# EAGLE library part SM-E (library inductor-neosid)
TRANSFORMER SMD converter and transformer acc. to customer specification

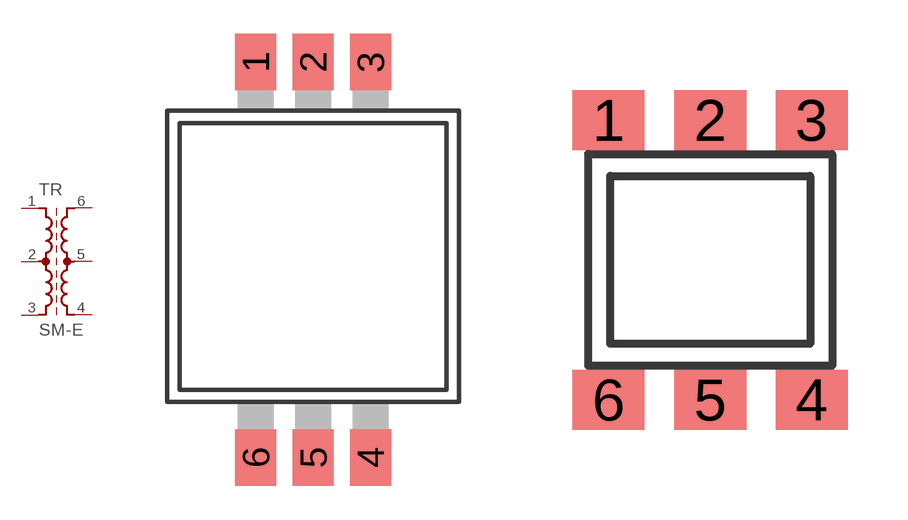
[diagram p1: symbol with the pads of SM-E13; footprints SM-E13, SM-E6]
Designator prefix TR

## SM-E13 (OC_FARNELL: unknown; OC_NEWARK: unknown)  [SM-E13]
1  1  pas
2  2  pas
3  3  pas
4  4  pas
5  5  pas
6  6  pas

## SM-E6 (OC_FARNELL: unknown; OC_NEWARK: unknown)  [SM-E6]
Pads as for SM-E13

## SM-E8 (OC_FARNELL: unknown; OC_NEWARK: unknown)  [SM-E8]
Pads as for SM-E13

## Footprint SM-E13 (pad centres in mm)
SMD CONVERTER/TRANSFORMER acc. to customer specification, 13 x 19.3 x 9 mm
smd 1.8 x 2.5: 1 -2.54,8.6; 2 0,8.6; 3 2.54,8.6; 4 2.54,-8.9; 5 0,-8.9; 6 -2.54,-8.9

## Footprint SM-E6 (pad centres in mm)
SMD CONVERTER/TRANSFORMER acc. to customer specification, 6.25 x 5.8 x 4.8 mm
smd 1.8 x 1.5: 1 -2.54,3.5; 2 0,3.5; 3 2.54,3.5; 4 2.54,-3.5; 5 0,-3.5; 6 -2.54,-3.5

## Footprint SM-E8 (pad centres in mm)
SMD CONVERTER/TRANSFORMER acc. to customer specification, 9.4 x 12.2 x 5.2 mm
smd 1.8 x 1.5: 1 -2.54,5.4; 2 0,5.4; 3 2.54,5.4; 4 2.54,-5.4; 5 0,-5.4; 6 -2.54,-5.4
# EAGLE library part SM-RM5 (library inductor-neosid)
TRANSFORMER SMD converter and transformer acc. to customer specification

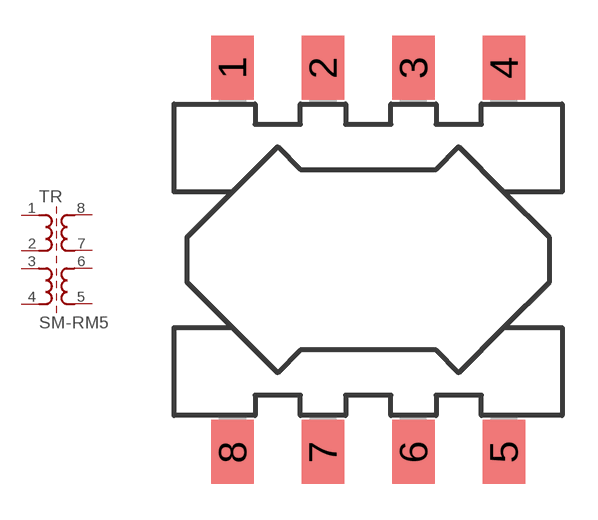
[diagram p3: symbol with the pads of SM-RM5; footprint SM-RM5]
Designator prefix TR

## SM-RM5 (OC_FARNELL: unknown; OC_NEWARK: unknown)  [SM-RM5]
1  1  pas
2  2  pas
3  3  pas
4  4  pas
5  5  pas
6  6  pas
7  7  pas
8  8  pas

## Footprint SM-RM5 (pad centres in mm)
SMD CONVERTER/TRANSFORMER acc. to customer specification, 16.5 x 19 x 10.6 mm
smd 1.8 x 2.7: 1 -5.715,8.1; 2 -1.905,8.1; 3 1.905,8.1; 4 5.715,8.1; 5 5.715,-8.1; 6 1.905,-8.1; 7 -1.905,-8.1; 8 -5.715,-8.1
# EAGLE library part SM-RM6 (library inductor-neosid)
TRANSFORMER SMD converter and transformer acc. to customer specification

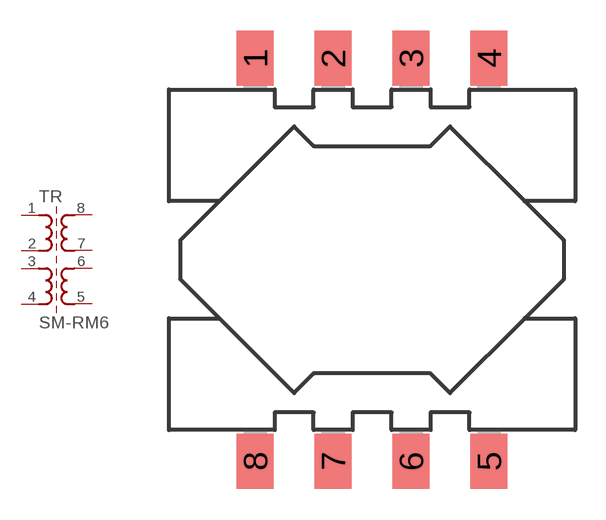
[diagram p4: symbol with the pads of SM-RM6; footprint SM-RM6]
Designator prefix TR

## SM-RM6 (OC_FARNELL: unknown; OC_NEWARK: unknown)  [SM-RM6]
1  1  pas
2  2  pas
3  3  pas
4  4  pas
5  5  pas
6  6  pas
7  7  pas
8  8  pas

## Footprint SM-RM6 (pad centres in mm)
SMD CONVERTER/TRANSFORMER acc. to customer specification, 20 x 22 x 12.6 mm
smd 1.8 x 2.7: 1 -5.715,9.85; 2 -1.905,9.85; 3 1.905,9.85; 4 5.715,9.85; 5 5.715,-9.85; 6 1.905,-9.85; 7 -1.905,-9.85; 8 -5.715,-9.85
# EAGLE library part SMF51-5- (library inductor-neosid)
RF TRANSFORMER SMD tunable RF transformer with tab

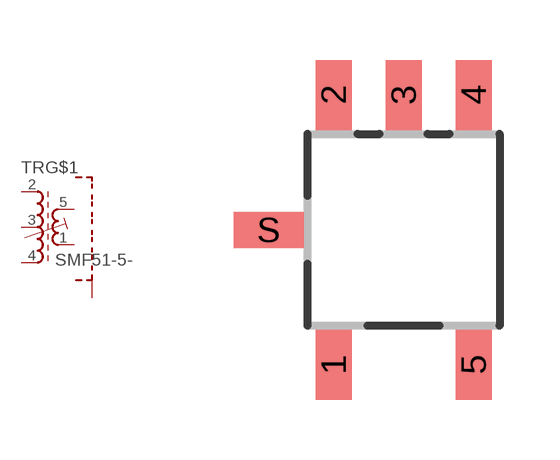
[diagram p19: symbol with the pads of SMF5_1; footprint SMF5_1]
Designator prefix TR; gates G$1=SMF51-4 G$2=SHIELD2

## SMF51-5-5124513 (OC_FARNELL: unknown; OC_NEWARK: unknown)  [SMF5_1]
1  G$1:E2  pas
2  G$1:A1  pas
3  G$1:Z  pas
4  G$1:E1  pas
5  G$1:A2  pas
S  G$2:S  pas

## SMF51-5-5125431 (OC_FARNELL: unknown; OC_NEWARK: unknown)  [SMF5_1]
1  G$1:Z  pas
2  G$1:A1  pas
3  G$1:E2  pas
4  G$1:A2  pas
5  G$1:E1  pas
S  G$2:S  pas

## Footprint SMF5_1 (pad centres in mm)
SMD TUNABLE RF COIL 5 x 5 mm
smd 0.9 x 1.75: 1 -1.75,-3.375; 2 -1.75,3.375; 3 0,3.375; 4 1.75,3.375; 5 1.75,-3.375
smd 1.75 x 0.9: S -3.375,0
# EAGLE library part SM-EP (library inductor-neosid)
TRANSFORMER SMD converter and transformer acc. to customer specification

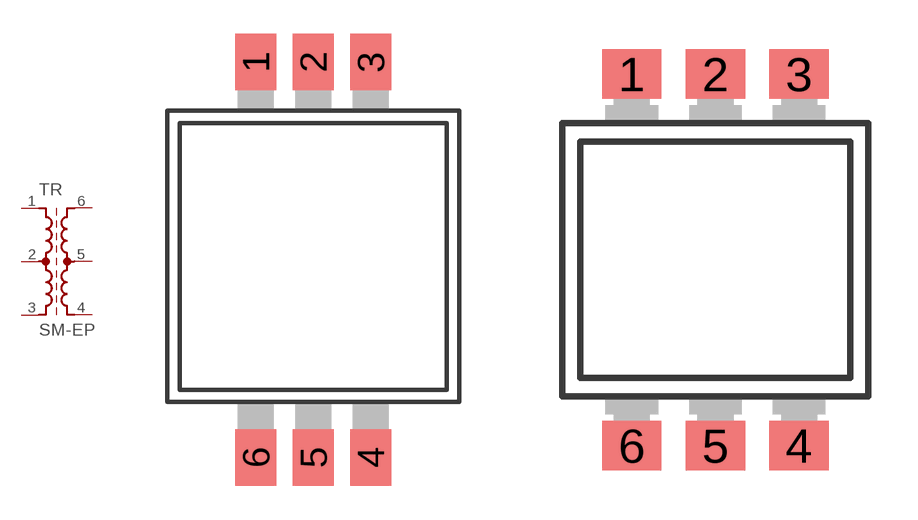
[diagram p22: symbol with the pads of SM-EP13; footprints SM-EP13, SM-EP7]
Designator prefix TR

## SM-EP13 (OC_FARNELL: unknown; OC_NEWARK: unknown)  [SM-EP13]
1  1  pas
2  2  pas
3  3  pas
4  4  pas
5  5  pas
6  6  pas

## SM-EP7 (OC_FARNELL: unknown; OC_NEWARK: unknown)  [SM-EP7]
Pads as for SM-EP13

## Footprint SM-EP13 (pad centres in mm)
SMD CONVERTER/TRANSFORMER acc. to customer specification, 12.8 x 19.4 x 12.3 mm
smd 1.8 x 2.5: 1 -2.54,8.6; 2 0,8.6; 3 2.54,8.6; 4 2.54,-8.9; 5 0,-8.9; 6 -2.54,-8.9

## Footprint SM-EP7 (pad centres in mm)
SMD CONVERTER/TRANSFORMER acc. to customer specification, 9.2 x 12.7 x 8.6 mm
smd 1.8 x 1.5: 1 -2.54,5.65; 2 0,5.65; 3 2.54,5.65; 4 2.54,-5.65; 5 0,-5.65; 6 -2.54,-5.65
